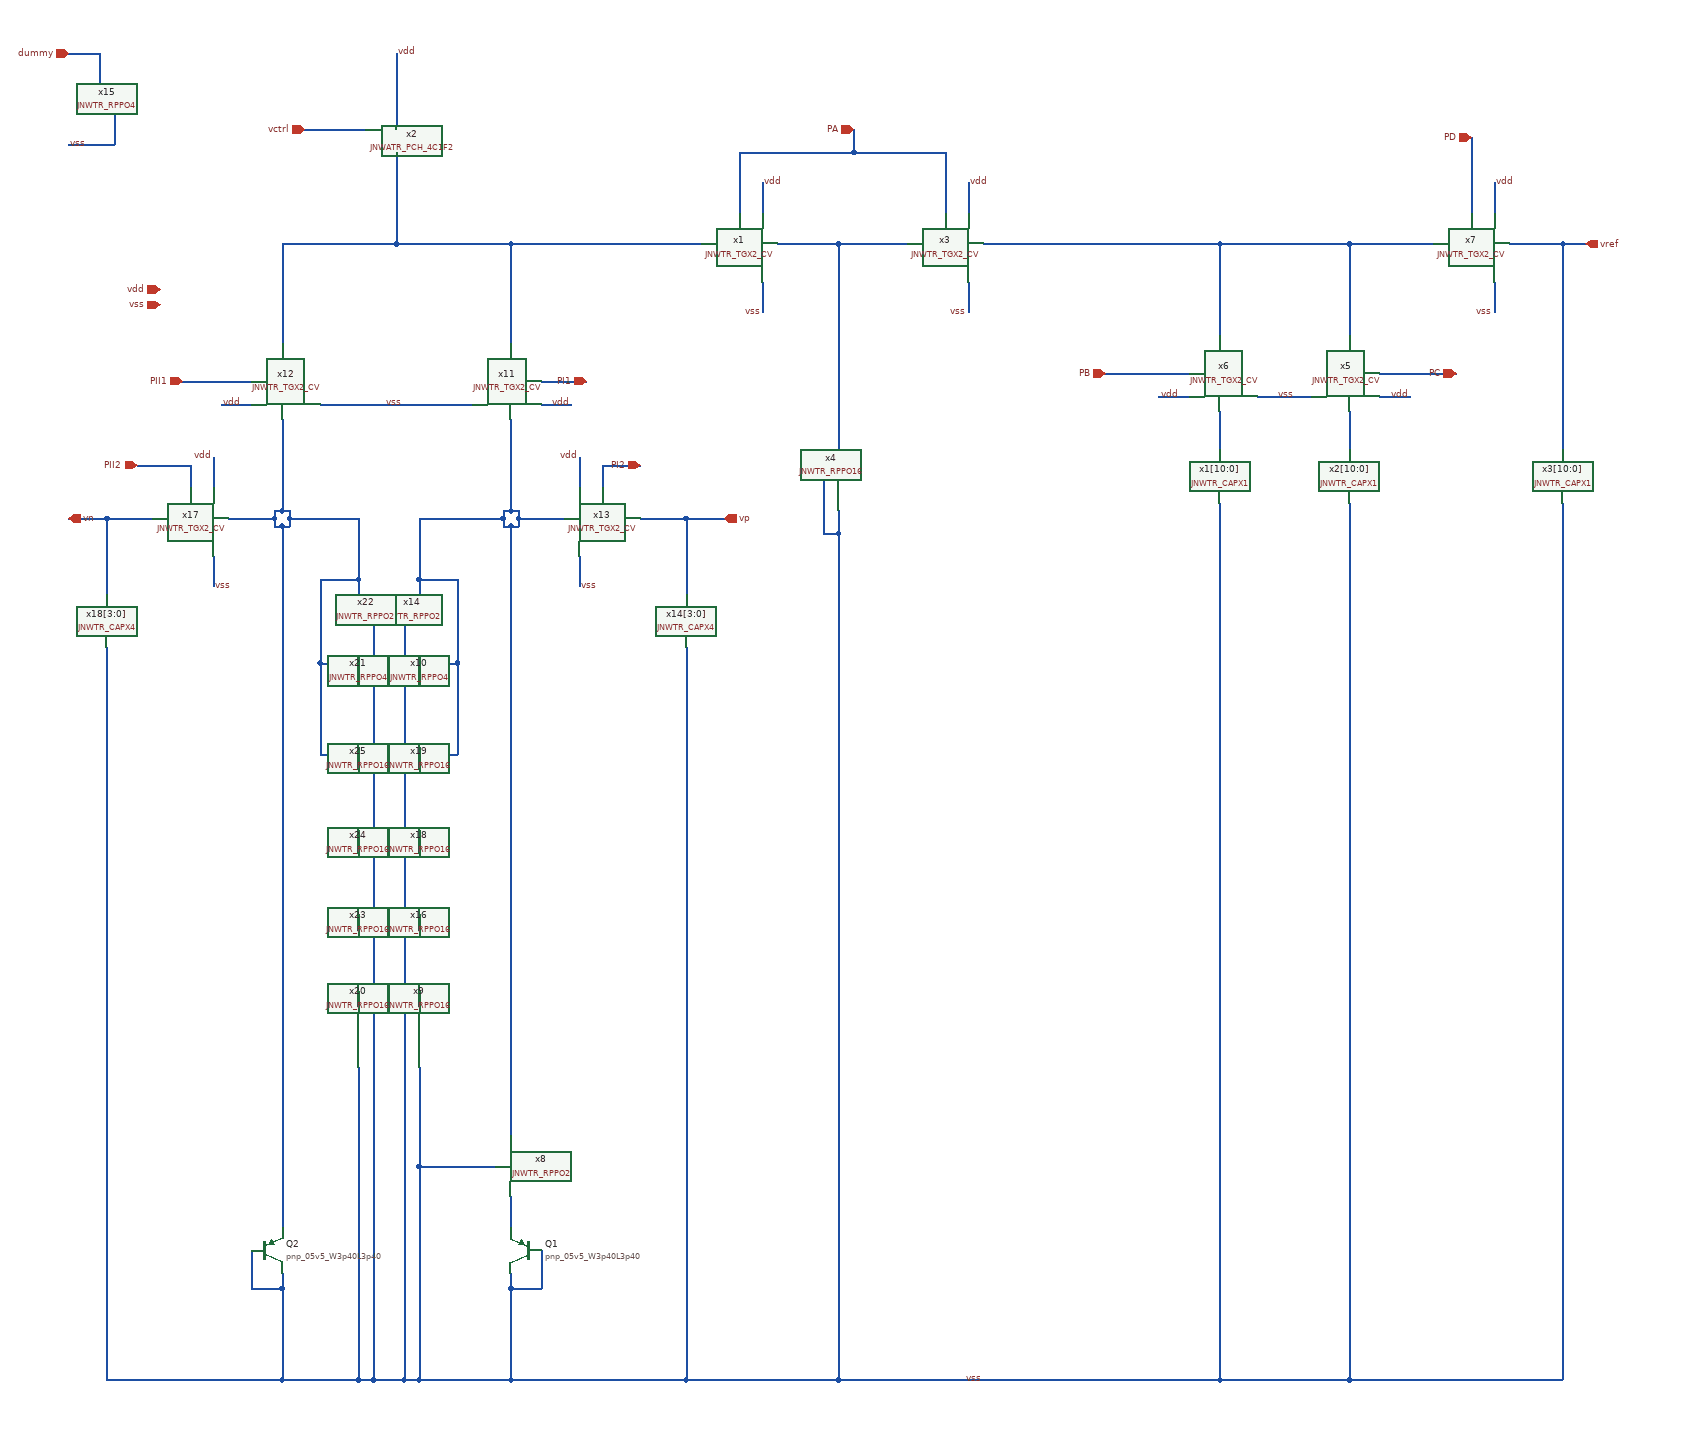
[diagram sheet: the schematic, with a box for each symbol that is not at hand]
v {xschem version=3.4.5 file_version=1.2
}
G {}
K {}
V {}
S {}
E {}
N 1370 -1540 1460 -1540 {
lab=#net1}
N 1290 -1540 1370 -1540 {
lab=#net1}
N 1370 -1540 1370 -1270 {
lab=#net1}
N 1350 -1230 1350 -1160 {
lab=vss}
N 1350 -1160 1370 -1160 {
lab=vss}
N 1370 -1190 1370 -1160 {
lab=vss}
N 1560 -1540 1870 -1540 {
lab=#net2}
N 1270 -1490 1270 -1450 {
lab=vss}
N 1270 -1620 1270 -1580 {
lab=vdd}
N 1240 -1660 1240 -1580 {
lab=PA}
N 1540 -1490 1540 -1450 {
lab=vss}
N 1540 -1620 1540 -1580 {
lab=vdd}
N 1510 -1660 1510 -1580 {
lab=PA}
N 1920 -1340 1990 -1340 {
lab=vss}
N 1790 -1340 1830 -1340 {
lab=vdd}
N 1870 -1540 1870 -1420 {
lab=#net2}
N 2040 -1540 2040 -1420 {
lab=#net2}
N 1720 -1370 1830 -1370 {
lab=PB}
N 2080 -1370 2180 -1370 {
lab=PC}
N 2080 -1340 2120 -1340 {
lab=vdd}
N 2040 -1540 2150 -1540 {
lab=#net2}
N 1870 -1540 2040 -1540 {
lab=#net2}
N 2230 -1490 2230 -1450 {
lab=vss}
N 2230 -1620 2230 -1580 {
lab=vdd}
N 2200 -1680 2200 -1580 {
lab=PD}
N 2250 -1540 2320 -1540 {
lab=vref}
N 2320 -1540 2320 -1270 {
lab=vref}
N 2040 -1320 2040 -1270 {
lab=#net3}
N 1870 -1320 1870 -1270 {
lab=#net4}
N 560 -1330 600 -1330 {
lab=vdd}
N 980 -1360 1040 -1360 {
lab=PI1}
N 980 -1330 1020 -1330 {
lab=vdd}
N 640 -1540 640 -1410 {
lab=#net5}
N 940 -1540 1190 -1540 {
lab=#net5}
N 640 -1540 790 -1540 {
lab=#net5}
N 940 -1540 940 -1410 {
lab=#net5}
N 790 -1540 940 -1540 {
lab=#net5}
N 690 -1330 890 -1330 {
lab=vss}
N 940 -1190 950 -1190 {
lab=#net6}
N 950 -1180 950 -1170 {
lab=#net6}
N 930 -1180 930 -1170 {
lab=#net6}
N 930 -1190 940 -1190 {
lab=#net6}
N 640 -1190 650 -1190 {
lab=#net7}
N 650 -1180 650 -1170 {
lab=#net7}
N 640 -1170 650 -1170 {
lab=#net7}
N 630 -1180 630 -1170 {
lab=#net7}
N 630 -1190 640 -1190 {
lab=#net7}
N 950 -1180 1010 -1180 {
lab=#net6}
N 950 -1190 950 -1180 {
lab=#net6}
N 940 -1310 940 -1190 {
lab=#net6}
N 640 -1310 640 -1190 {
lab=#net7}
N 1170 -1180 1220 -1180 {
lab=vp}
N 1170 -1180 1170 -1080 {
lab=vp}
N 1110 -1180 1170 -1180 {
lab=vp}
N 1370 -1160 1370 -50 {
lab=vss}
N 650 -1190 650 -1180 {
lab=#net7}
N 930 -1190 930 -1180 {
lab=#net6}
N 630 -1170 640 -1170 {
lab=#net7}
N 640 -1170 640 -250 {
lab=#net7}
N 650 -1180 740 -1180 {
lab=#net7}
N 570 -1180 630 -1180 {
lab=#net7}
N 360 -1180 410 -1180 {
lab=vn}
N 410 -1180 410 -1080 {
lab=vn}
N 410 -1180 470 -1180 {
lab=vn}
N 630 -1190 630 -1180 {
lab=#net7}
N 410 -1010 410 -50 {
lab=vss}
N 2040 -50 2320 -50 {
lab=vss}
N 2320 -1200 2320 -50 {
lab=vss}
N 2040 -1200 2040 -50 {
lab=vss}
N 1870 -50 2040 -50 {
lab=vss}
N 1870 -1200 1870 -50 {
lab=vss}
N 1370 -50 1870 -50 {
lab=vss}
N 1170 -1010 1170 -50 {
lab=vss}
N 940 -50 1170 -50 {
lab=vss}
N 1170 -50 1370 -50 {
lab=vss}
N 940 -170 940 -50 {
lab=vss}
N 640 -170 640 -50 {
lab=vss}
N 410 -50 640 -50 {
lab=vss}
N 600 -220 600 -170 {
lab=vss}
N 600 -170 640 -170 {
lab=vss}
N 980 -220 980 -170 {
lab=vss}
N 940 -170 980 -170 {
lab=vss}
N 940 -190 940 -170 {
lab=vss}
N 1030 -1130 1030 -1090 {
lab=vss}
N 550 -1130 550 -1090 {
lab=vss}
N 1030 -1260 1030 -1220 {
lab=vdd}
N 550 -1260 550 -1220 {
lab=vdd}
N 790 -1660 790 -1540 {
lab=#net5}
N 670 -1690 750 -1690 {
lab=vctrl}
N 790 -1790 790 -1690 {
lab=vdd}
N 520 -1250 520 -1220 {
lab=PII2}
N 450 -1250 520 -1250 {
lab=PII2}
N 1060 -1250 1060 -1220 {
lab=PI2}
N 1060 -1250 1110 -1250 {
lab=PI2}
N 2320 -1540 2350 -1540 {
lab=vref}
N 1390 -1660 1510 -1660 {
lab=PA}
N 1390 -1690 1390 -1660 {
lab=PA}
N 1240 -1660 1390 -1660 {
lab=PA}
N 740 -1100 740 -1080 {
lab=#net7}
N 510 -1360 600 -1360 {
lab=PII1}
N 360 -1790 400 -1790 {
lab=dummy}
N 400 -1790 400 -1750 {
lab=dummy}
N 420 -1710 420 -1670 {
lab=vss}
N 360 -1670 420 -1670 {
lab=vss}
N 940 -1170 950 -1170 {
lab=#net6}
N 640 -190 640 -170 {
lab=vss}
N 820 -770 820 -740 {
lab=#net8}
N 820 -330 820 -50 {
lab=vss}
N 820 -870 820 -850 {
lab=#net6}
N 820 -990 820 -960 {
lab=#net6}
N 820 -660 820 -640 {
lab=#net9}
N 820 -560 820 -540 {
lab=#net10}
N 820 -1100 870 -1100 {
lab=#net6}
N 870 -1100 870 -990 {
lab=#net6}
N 820 -990 870 -990 {
lab=#net6}
N 870 -990 870 -870 {
lab=#net6}
N 820 -870 870 -870 {
lab=#net6}
N 820 -1000 820 -990 {
lab=#net6}
N 820 -880 820 -870 {
lab=#net6}
N 820 -1100 820 -1080 {
lab=#net6}
N 820 -1180 820 -1100 {
lab=#net6}
N 820 -1180 930 -1180 {
lab=#net6}
N 800 -1040 800 -50 {
lab=vss}
N 820 -50 940 -50 {
lab=vss}
N 800 -50 820 -50 {
lab=vss}
N 740 -770 740 -740 {
lab=#net11}
N 740 -870 740 -850 {
lab=#net7}
N 740 -990 740 -960 {
lab=#net7}
N 740 -660 740 -640 {
lab=#net12}
N 740 -560 740 -540 {
lab=#net13}
N 690 -1100 740 -1100 {
lab=#net7}
N 690 -1100 690 -990 {
lab=#net7}
N 690 -990 740 -990 {
lab=#net7}
N 690 -990 690 -870 {
lab=#net7}
N 690 -870 740 -870 {
lab=#net7}
N 740 -1000 740 -990 {
lab=#net7}
N 740 -880 740 -870 {
lab=#net7}
N 740 -1180 740 -1100 {
lab=#net7}
N 740 -460 740 -50 {
lab=vss}
N 640 -50 740 -50 {
lab=vss}
N 760 -50 800 -50 {
lab=vss}
N 820 -330 920 -330 {
lab=vss}
N 820 -460 820 -330 {
lab=vss}
N 940 -1170 940 -370 {
lab=#net6}
N 930 -1170 940 -1170 {
lab=#net6}
N 940 -290 940 -250 {
lab=#net14}
N 760 -1040 760 -50 {
lab=vss}
N 740 -50 760 -50 {
lab=vss}
C {devices/ipin.sym} 480 -1480 0 0 {name=p1 lab=vdd}
C {devices/ipin.sym} 480 -1460 0 0 {name=p2 lab=vss
}
C {JNW_TR_SKY130A/JNWTR_TGX2_CV.sym} 1180 -1540 0 0 {name=x1 }
C {devices/lab_wire.sym} 1560 -50 0 0 {name=p4 sig_type=std_logic lab=vss
}
C {devices/lab_wire.sym} 1270 -1450 0 0 {name=p5 sig_type=std_logic lab=vss
}
C {devices/lab_wire.sym} 1270 -1620 0 1 {name=p6 sig_type=std_logic lab=vdd

}
C {JNW_TR_SKY130A/JNWTR_TGX2_CV.sym} 1450 -1540 0 0 {name=x3 }
C {devices/lab_wire.sym} 1970 -1340 0 0 {name=p7 sig_type=std_logic lab=vss
}
C {JNW_TR_SKY130A/JNWTR_TGX2_CV.sym} 2040 -1430 1 0 {name=x5 }
C {JNW_TR_SKY130A/JNWTR_TGX2_CV.sym} 1870 -1430 3 1 {name=x6 }
C {devices/lab_wire.sym} 1540 -1450 0 0 {name=p9 sig_type=std_logic lab=vss
}
C {devices/lab_wire.sym} 1540 -1620 0 1 {name=p11 sig_type=std_logic lab=vdd

}
C {devices/lab_wire.sym} 1790 -1340 0 1 {name=p12 sig_type=std_logic lab=vdd

}
C {devices/lab_wire.sym} 2120 -1340 0 0 {name=p13 sig_type=std_logic lab=vdd

}
C {JNW_TR_SKY130A/JNWTR_TGX2_CV.sym} 2140 -1540 0 0 {name=x7 }
C {devices/lab_wire.sym} 2230 -1450 0 0 {name=p14 sig_type=std_logic lab=vss
}
C {devices/lab_wire.sym} 2230 -1620 0 1 {name=p17 sig_type=std_logic lab=vdd

}
C {devices/lab_wire.sym} 800 -1330 0 0 {name=p18 sig_type=std_logic lab=vss
}
C {JNW_TR_SKY130A/JNWTR_TGX2_CV.sym} 940 -1420 1 0 {name=x11 }
C {JNW_TR_SKY130A/JNWTR_TGX2_CV.sym} 640 -1420 3 1 {name=x12 }
C {devices/lab_wire.sym} 560 -1330 0 1 {name=p19 sig_type=std_logic lab=vdd

}
C {devices/lab_wire.sym} 1020 -1330 0 0 {name=p20 sig_type=std_logic lab=vdd

}
C {JNW_TR_SKY130A/JNWTR_TGX2_CV.sym} 1120 -1180 0 1 {name=x13 }
C {JNW_TR_SKY130A/JNWTR_CAPX4.sym} 1170 -1020 0 0 {name=x14[3:0]}
C {JNW_TR_SKY130A/JNWTR_TGX2_CV.sym} 460 -1180 0 0 {name=x17 }
C {JNW_TR_SKY130A/JNWTR_CAPX4.sym} 410 -1020 0 1 {name=x18[3:0]}
C {sky130_fd_pr/pnp_05v5.sym} 960 -220 0 1 {name=Q1
model=pnp_05v5_W3p40L3p40
m=8
spiceprefix=X
}
C {sky130_fd_pr/pnp_05v5.sym} 620 -220 0 0 {name=Q2
model=pnp_05v5_W3p40L3p40
m=1
spiceprefix=X
}
C {devices/lab_wire.sym} 1030 -1090 0 1 {name=p23 sig_type=std_logic lab=vss
}
C {devices/lab_wire.sym} 550 -1090 0 1 {name=p24 sig_type=std_logic lab=vss
}
C {devices/lab_wire.sym} 1030 -1260 0 0 {name=p25 sig_type=std_logic lab=vdd

}
C {devices/lab_wire.sym} 550 -1260 0 0 {name=p26 sig_type=std_logic lab=vdd

}
C {devices/ipin.sym} 670 -1690 0 0 {name=p27 lab=vctrl}
C {devices/lab_wire.sym} 790 -1790 0 1 {name=p28 sig_type=std_logic lab=vdd

}
C {JNW_ATR_SKY130A/JNWATR_PCH_4C1F2.sym} 750 -1690 0 0 {name=x2 }
C {devices/ipin.sym} 2200 -1680 1 0 {name=p8 lab=PD}
C {devices/ipin.sym} 1720 -1370 0 0 {name=p10 lab=PB}
C {devices/ipin.sym} 2180 -1370 2 0 {name=p15 lab=PC}
C {devices/ipin.sym} 1390 -1690 1 0 {name=p16 lab=PA}
C {devices/ipin.sym} 1110 -1250 2 0 {name=p31 lab=PI2}
C {devices/ipin.sym} 360 -1790 0 0 {name=p32 lab=dummy}
C {devices/ipin.sym} 510 -1360 0 0 {name=p33 lab=PII1}
C {devices/ipin.sym} 1040 -1360 2 0 {name=p34 lab=PI1}
C {devices/opin.sym} 2350 -1540 0 0 {name=p3 lab=vref}
C {devices/opin.sym} 1220 -1180 0 0 {name=p21 lab=vp}
C {devices/opin.sym} 360 -1180 2 0 {name=p22 lab=vn}
C {JNW_TR_SKY130A/JNWTR_RPPO16.sym} 1370 -1270 1 0 {name=x4 }
C {devices/ipin.sym} 450 -1250 0 0 {name=p29 lab=PII2}
C {JNW_TR_SKY130A/JNWTR_RPPO4.sym} 400 -1750 3 1 {name=x15 }
C {devices/lab_wire.sym} 360 -1670 0 1 {name=p30 sig_type=std_logic lab=vss
}
C {JNW_TR_SKY130A/JNWTR_CAPX1.sym} 1870 -1210 0 0 {name=x1[10:0]}
C {JNW_TR_SKY130A/JNWTR_CAPX1.sym} 2040 -1210 0 0 {name=x2[10:0]}
C {JNW_TR_SKY130A/JNWTR_CAPX1.sym} 2320 -1210 0 0 {name=x3[10:0]}
C {JNW_TR_SKY130A/JNWTR_RPPO16.sym} 820 -540 1 0 {name=x9 }
C {JNW_TR_SKY130A/JNWTR_RPPO4.sym} 820 -960 1 0 {name=x10 }
C {JNW_TR_SKY130A/JNWTR_RPPO2.sym} 820 -1080 1 0 {name=x14 }
C {JNW_TR_SKY130A/JNWTR_RPPO16.sym} 820 -640 1 0 {name=x16 }
C {JNW_TR_SKY130A/JNWTR_RPPO16.sym} 820 -740 1 0 {name=x18 }
C {JNW_TR_SKY130A/JNWTR_RPPO16.sym} 820 -850 1 0 {name=x19 }
C {JNW_TR_SKY130A/JNWTR_RPPO16.sym} 740 -540 3 1 {name=x20 }
C {JNW_TR_SKY130A/JNWTR_RPPO4.sym} 740 -960 3 1 {name=x21 }
C {JNW_TR_SKY130A/JNWTR_RPPO2.sym} 740 -1080 3 1 {name=x22 }
C {JNW_TR_SKY130A/JNWTR_RPPO16.sym} 740 -640 3 1 {name=x23 }
C {JNW_TR_SKY130A/JNWTR_RPPO16.sym} 740 -740 3 1 {name=x24 }
C {JNW_TR_SKY130A/JNWTR_RPPO16.sym} 740 -850 3 1 {name=x25 }
C {JNW_TR_SKY130A/JNWTR_RPPO2.sym} 940 -370 1 0 {name=x8 }
